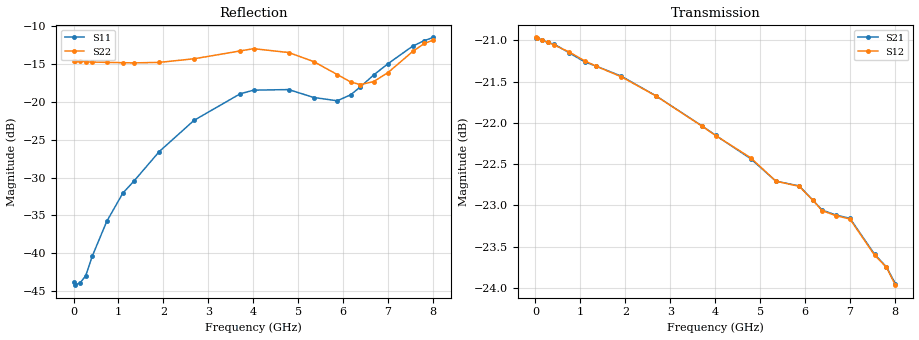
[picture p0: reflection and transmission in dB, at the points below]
! DEVICE ID: PE43712
! File Path: z:\PE43713\PE43713_CHAR_NOM_04292014\AMB\3p300\LS_ATT_19p75dB\PE43713_AMB_3p300V_3p000V_0p000V_LS_ATT_19p75dB_S2P_SN_10_A0139A.s2p
! Serial: 10
! Lot: A0139A
! Temp: 25C
! VDD: 3.300
! VSS: 0.000
! Control_Hi: 3.000
! Control_Lo: 0.000
! Attenuation Step: 19.75dB
! Port 1: RF1
! Port 2: RF2
! ThroughPath:1-2
! IDD: 0.0001468615
! ISS: -1.843e-007
#  Hz  S  RI  R  50
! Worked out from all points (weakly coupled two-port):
!   801 points, 10 MHz to 8.01 GHz, reference 50 ohm
!   highest |S21| = -20.97 dB at 10 MHz (marker M1); lowest = -24.0 dB at 8.01 GHz (marker M2)
!   lowest |S11| = -44.2 dB at 30 MHz (marker M3), VSWR 1.01, Z = 49.4 + j0.136 ohm
!   |S11| at or under -10 dB: start of sweep to end of sweep
!   |S22| runs from -17.8 to -11.8 dB; largest |S21 - S12| = 0.00034
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1e7  -0.0064 0.000561  0.0894 -0.000436  0.0895 -0.000416  -0.1874 0.00123
3e7  -0.00601 0.00137  0.0894 -0.00113  0.0894 -0.00113  -0.1869 0.003
1.5e8  -0.00518 0.00374  0.089 -0.00526  0.089 -0.00526  -0.1853 0.0113
2.7e8  -0.0045 0.00548  0.0884 -0.00923  0.0884 -0.00927  -0.1836 0.018
4.2e8  -0.00414 0.00868  0.0875 -0.0142  0.0874 -0.0142  -0.1815 0.0265
7.4e8  -0.00382 0.0158  0.0843 -0.0239  0.0844 -0.0239  -0.1763 0.0464
1.1e9  -0.00242 0.0249  0.0796 -0.0338  0.0797 -0.0339  -0.1686 0.0672
1.35e9  9.2e-06 0.0301  0.076 -0.0402  0.076 -0.0402  -0.1624 0.0798
1.91e9  0.00872 0.0462  0.0661 -0.0531  0.066 -0.0531  -0.1433 0.1128
2.68e9  0.0268 0.0705  0.0488 -0.0665  0.0488 -0.0665  -0.1105 0.1577
3.71e9  0.0389 0.1062  0.0222 -0.0759  0.0221 -0.0759  -0.0828 0.2006
4.01e9  0.0401 0.1126  0.0145 -0.0767  0.0144 -0.0767  -0.0811 0.2095
4.79e9  0.0437 0.1124  -0.00478 -0.0754  -0.00476 -0.0755  -0.0656 0.2014
5.35e9  0.0562 0.0909  -0.0171 -0.0712  -0.0171 -0.0712  -0.0484 0.1779
5.87e9  0.0769 0.0666  -0.0283 -0.067  -0.0282 -0.067  -0.0101 0.1512
6.17e9  0.0952 0.0579  -0.0349 -0.0622  -0.0347 -0.0623  0.02 0.1338
6.38e9  0.1123 0.0555  -0.0378 -0.0593  -0.0377 -0.0593  0.0445 0.1223
6.68e9  0.1412 0.0521  -0.0428 -0.0552  -0.0427 -0.0552  0.0817 0.1088
7e9  0.1705 0.0536  -0.0485 -0.0498  -0.0484 -0.0498  0.1166 0.1039
7.55e9  0.2251 0.0625  -0.0545 -0.0374  -0.0544 -0.0374  0.183 0.1134
7.81e9  0.2442 0.0701  -0.0562 -0.0326  -0.0561 -0.0327  0.2105 0.1218
8.01e9  0.2555 0.0764  -0.0566 -0.0287  -0.0564 -0.0288  0.2239 0.1248
